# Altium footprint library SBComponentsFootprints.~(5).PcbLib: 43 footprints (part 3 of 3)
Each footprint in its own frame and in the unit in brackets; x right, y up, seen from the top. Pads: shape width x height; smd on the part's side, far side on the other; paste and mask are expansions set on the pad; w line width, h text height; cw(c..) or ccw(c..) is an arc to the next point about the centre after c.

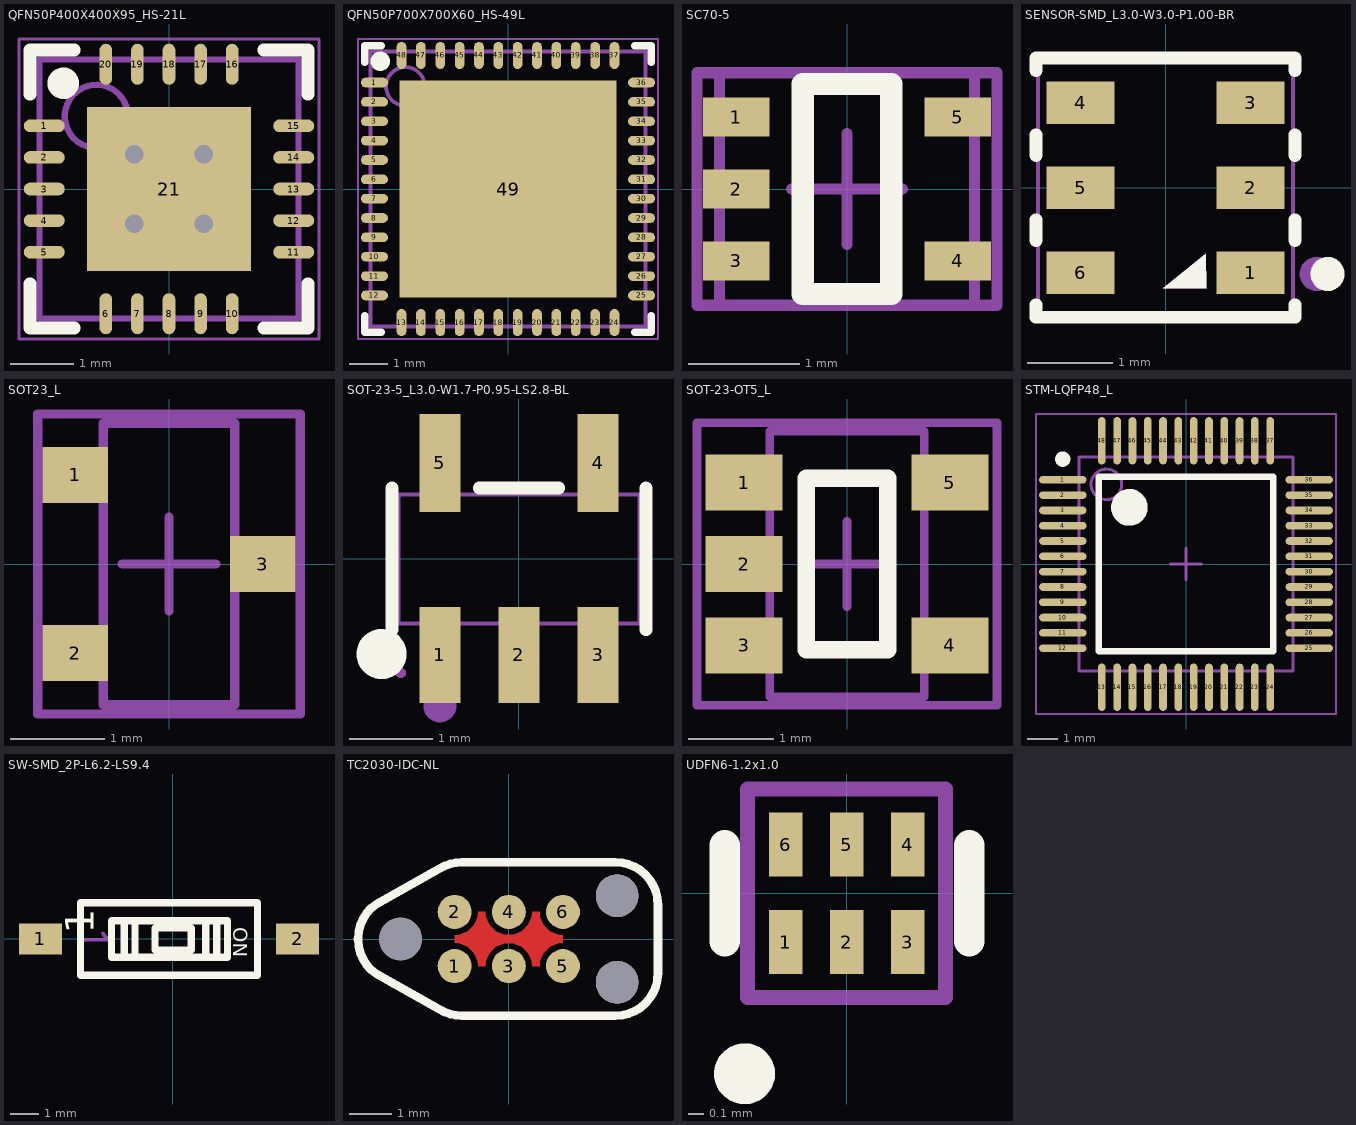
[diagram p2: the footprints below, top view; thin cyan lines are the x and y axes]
## QFN50P400X400X95_HS-21L [mm] "QFN, 20-Leads, Body 4,00x4,00mm, Pitch 0,50mm, Thermal Pad 2,60x2,60mm, IPC High Density"
height 0.95
pads (21):
  oval 0.65x0.2 smd: 1(-1.975,1) 2(-1.975,0.5) 3(-1.975,0) 4(-1.975,-0.5) 5(-1.975,-1) 11(1.975,-1) 12(1.975,-0.5) 13(1.975,0) 14(1.975,0.5) 15(1.975,1)
  oval 0.2x0.65 smd: 6(-1,-1.975) 7(-0.5,-1.975) 8(0,-1.975) 9(0.5,-1.975) 10(1,-1.975) 16(1,1.975) 17(0.5,1.975) 18(0,1.975) 19(-0.5,1.975) 20(-1,1.975)
  rect 2.6x2.6 smd: 21(0,0)
via -0.55,0.55 diameter 0.6 hole 0.3
via 0.55,0.55 diameter 0.6 hole 0.3
via -0.55,-0.55 diameter 0.6 hole 0.3
via 0.55,-0.55 diameter 0.6 hole 0.3
Top Overlay:
  circle w0.25: c-1.675,1.675 r0.125
  lines w0.2: -2.2,-1.5 -2.2,-2.2 -1.5,-2.2 ; -2.2,1.5 -2.2,2.2 -1.5,2.2 ; 1.5,-2.2 2.2,-2.2 2.2,-1.5 ; 1.5,2.2 2.2,2.2 2.2,1.5
Mechanical 13:
  circle w0.1: c-1.15,1.15 r0.5
  lines w0.1: -2.05,-2.05 -2.05,2.05 2.05,2.05 2.05,-2.05 -2.05,-2.05
Mechanical 15:
  lines w0.05: -2.375,-2.375 -2.375,2.375 2.375,2.375 2.375,-2.375 -2.375,-2.375
  lines w0.1: -0.5,0 0.5,0 ; 0,-0.5 0,0.5
3D body: height 0.95, standoff 0.05, extent -2.05,-2.05 2.05,2.05

## QFN50P700X700X60_HS-49L [mm] "QFN, 48-Leads, Body 7,00x7,00mm, Pitch 0,50mm, Thermal Pad 5,60x5,60mm, IPC High Density"
height 0.6
pads (49):
  oval 0.7x0.25 smd: 1(-3.45,2.75) 2(-3.45,2.25) 3(-3.45,1.75) 4(-3.45,1.25) 5(-3.45,0.75) 6(-3.45,0.25) 7(-3.45,-0.25) 8(-3.45,-0.75) 9(-3.45,-1.25) 10(-3.45,-1.75) 11(-3.45,-2.25) 12(-3.45,-2.75) 25(3.45,-2.75) 26(3.45,-2.25) 27(3.45,-1.75) 28(3.45,-1.25) 29(3.45,-0.75) 30(3.45,-0.25) 31(3.45,0.25) 32(3.45,0.75) 33(3.45,1.25) 34(3.45,1.75) 35(3.45,2.25) 36(3.45,2.75)
  oval 0.25x0.7 smd: 13(-2.75,-3.45) 14(-2.25,-3.45) 15(-1.75,-3.45) 16(-1.25,-3.45) 17(-0.75,-3.45) 18(-0.25,-3.45) 19(0.25,-3.45) 20(0.75,-3.45) 21(1.25,-3.45) 22(1.75,-3.45) 23(2.25,-3.45) 24(2.75,-3.45) 37(2.75,3.45) 38(2.25,3.45) 39(1.75,3.45) 40(1.25,3.45) 41(0.75,3.45) 42(0.25,3.45) 43(-0.25,3.45) 44(-0.75,3.45) 45(-1.25,3.45) 46(-1.75,3.45) 47(-2.25,3.45) 48(-2.75,3.45)
  rect 5.6x5.6 smd: 49(0,0)
Top Overlay:
  circle w0.25: c-3.3,3.3 r0.125
  lines w0.2: -3.7,-3.275 -3.7,-3.7 -3.275,-3.7 ; -3.7,3.275 -3.7,3.7 -3.275,3.7 ; 3.275,-3.7 3.7,-3.7 3.7,-3.275 ; 3.275,3.7 3.7,3.7 3.7,3.275
Mechanical 13:
  circle w0.1: c-2.65,2.65 r0.5
  lines w0.1: -3.55,-3.55 -3.55,3.55 3.55,3.55 3.55,-3.55 -3.55,-3.55
Mechanical 15:
  lines w0.05: -3.875,-3.875 -3.875,3.875 3.875,3.875 3.875,-3.875 -3.875,-3.875
  lines w0.1: -0.5,0 0.5,0 ; 0,-0.5 0,0.5
3D body: height 0.6, standoff 0.05, extent -3.55,-3.55 3.55,3.55

## SC70-5 [mm]
height 1.1
pads (5):
  rect 0.6x0.35 smd: 1(-1,0.65) 2(-1,0) 3(-1,-0.65) 4(1,-0.65) 5(1,0.65)
Top Overlay:
  lines w0.2: -0.4,-0.95 -0.4,0.95 0.4,0.95 0.4,-0.95 -0.4,-0.95
Mechanical 13:
  lines w0.1: -1.15,-1.05 1.15,-1.05 1.15,1.05 -1.15,1.05 -1.15,-1.05
Mechanical 15:
  lines w0.1: -0.5,0 0.5,0 ; 0,-0.5 0,0.5 ; -1.355,-1.05 1.355,-1.05 1.355,1.05 -1.355,1.05 -1.355,-1.05
3D body "User Library-sot353.step": height 1, standoff 0, extent -1.15,-1.05 1.15,1.05

## SENSOR-SMD_L3.0-W3.0-P1.00-BR [mm]
pads (6):
  rect 0.8x0.5 smd paste+0 mask+0.05: 1(1,-1) 2(1,0) 3(1,1) 4(-1,1) 5(-1,0) 6(-1,-1)
Top Overlay:
  circle w0.2: c1.905,-1.016 r0.1
  region: -0.028,-1.186 0.481,-1.187 0.476,-0.78
  lines w0.15: -1.524,-1.378 -1.524,-1.524 1.524,-1.524 1.524,-1.378 ; -1.524,-0.622 -1.524,-0.378 ; -1.524,0.378 -1.524,0.622 ; -1.524,1.378 -1.524,1.524 1.524,1.524 1.524,1.378 ; 1.524,-0.622 1.524,-0.378 ; 1.524,0.378 1.524,0.622
Mechanical 6:
  circle w0.2: c1.778,-1.016 r0.1
  region: -0.032,-1.186 0.477,-1.187 0.472,-0.781
Mechanical 15:
  region: 1.56,-1.5 1.559,-1.476 1.524,-1.443 1.476,-1.443 1.441,-1.476 1.44,-1.5 1.441,-1.524 1.476,-1.557 1.524,-1.557 1.559,-1.524
  region: -0.725,0.8 -1.275,0.8 -1.275,1.2 -0.725,1.2
  region: -0.725,-0.2 -1.275,-0.2 -1.275,0.2 -0.725,0.2
  region: -0.725,-1.2 -1.275,-1.2 -1.275,-0.8 -0.725,-0.8
  region: 1.275,-1.2 0.725,-1.2 0.725,-0.8 1.275,-0.8
  region: 1.275,-0.2 0.725,-0.2 0.725,0.2 1.275,0.2
  region: 1.275,0.8 0.725,0.8 0.725,1.2 1.275,1.2
  lines w0.051: -1.5,-1.5 -1.5,1.5 1.5,1.5 1.5,-1.5 -1.5,-1.5

## SOT23_L [mm] "SOT23, 3-Leads, Body 2.9x1.3mm, Pitch 0.95mm, Lead Span 2.3mm - Reverse Pinning, IPC High Density"
height 1.1
pads (3):
  rect 0.7x0.6 smd: 1(-1,0.95) 2(-1,-0.95) 3(1,0)
Mechanical 13:
  lines w0.1: -0.7,-1.5 0.7,-1.5 0.7,1.5 -0.7,1.5 -0.7,-1.5
Mechanical 15:
  lines w0.1: -0.5,0 0.5,0 ; 0,-0.5 0,0.5 ; -1.4,-1.6 1.4,-1.6 1.4,1.6 -1.4,1.6 -1.4,-1.6
3D body "SOT23.STEP": height 1.21, standoff -0.01, extent -1.125,-1.5 1.126,1.5

## SOT-23-5_L3.0-W1.7-P0.95-LS2.8-BL [mm]
pads (5):
  rect 0.49x1.157 smd: 1(-0.95,-1.154) 2(0,-1.154) 3(0.95,-1.154)
  rect 0.49x1.175 smd: 4(0.95,1.154) 5(-0.95,1.154)
Top Overlay:
  circle w0.3: c-1.651,-1.143 r0.15
  lines w0.152: -1.526,-0.851 -1.526,0.851 ; -0.476,0.851 0.476,0.851 ; 1.526,-0.851 1.526,0.851
Mechanical 6:
  circle w0.2: c-0.95,-1.763 r0.1
Mechanical 15:
  region: -1.36,-1.37 -1.361,-1.345 -1.396,-1.311 -1.445,-1.311 -1.48,-1.346 -1.48,-1.37 -1.48,-1.395 -1.445,-1.429 -1.396,-1.429 -1.361,-1.394
  region: -1.125,0.74 -1.125,1.01 -0.775,1.01 -0.775,0.74
  region: -1.125,1 -1.125,1.4 -0.775,1.4 -0.775,1
  region: 0.775,0.74 0.775,1.01 1.125,1.01 1.125,0.74
  region: 0.775,1 0.775,1.4 1.125,1.4 1.125,1
  region: 0.775,-1.01 0.775,-0.74 1.125,-0.74 1.125,-1.01
  region: 0.775,-1.4 0.775,-1 1.125,-1 1.125,-1.4
  region: -0.175,-1.01 -0.175,-0.74 0.175,-0.74 0.175,-1.01
  region: -0.175,-1.4 -0.175,-1 0.175,-1 0.175,-1.4
  region: -1.125,-1.01 -1.125,-0.74 -0.775,-0.74 -0.775,-1.01
  region: -1.125,-1.4 -1.125,-1 -0.775,-1 -0.775,-1.4
  lines w0.051: -1.45,-0.775 1.45,-0.775 1.45,0.775 -1.45,0.775 -1.45,-0.775

## SOT-23-OT5_L [mm] "SOT23, 5-Leads, Body 2.9x1.6mm, Pitch 0.95mm, Lead Span 2.7mm, IPC High Density"
height 1.45
pads (5):
  rect 0.9x0.65 smd: 1(-1.2,0.95) 2(-1.2,0) 3(-1.2,-0.95) 4(1.2,-0.95) 5(1.2,0.95)
Top Overlay:
  lines w0.2: -0.475,-1 -0.475,1 0.475,1 0.475,-1 -0.475,-1
Mechanical 13:
  lines w0.1: -0.9,-1.55 0.9,-1.55 0.9,1.55 -0.9,1.55 -0.9,-1.55
Mechanical 15:
  lines w0.1: -0.5,0 0.5,0 ; 0,-0.5 0,0.5 ; -1.75,-1.65 1.75,-1.65 1.75,1.65 -1.75,1.65 -1.75,-1.65
3D body: height 1.45, standoff 0, extent -0.9,-1.55 0.9,1.55

## STM-LQFP48_L [mm] "QFP, 48-Leads, Body 7x7mm, Pitch 0.5mm, IPC High Density"
height 1.6
pads (48):
  oval 1.55x0.25 smd: 1(-4.025,2.75) 2(-4.025,2.25) 3(-4.025,1.75) 4(-4.025,1.25) 5(-4.025,0.75) 6(-4.025,0.25) 7(-4.025,-0.25) 8(-4.025,-0.75) 9(-4.025,-1.25) 10(-4.025,-1.75) 11(-4.025,-2.25) 12(-4.025,-2.75) 25(4.025,-2.75) 26(4.025,-2.25) 27(4.025,-1.75) 28(4.025,-1.25) 29(4.025,-0.75) 30(4.025,-0.25) 31(4.025,0.25) 32(4.025,0.75) 33(4.025,1.25) 34(4.025,1.75) 35(4.025,2.25) 36(4.025,2.75)
  oval 0.25x1.55 smd: 13(-2.75,-4.025) 14(-2.25,-4.025) 15(-1.75,-4.025) 16(-1.25,-4.025) 17(-0.75,-4.025) 18(-0.25,-4.025) 19(0.25,-4.025) 20(0.75,-4.025) 21(1.25,-4.025) 22(1.75,-4.025) 23(2.25,-4.025) 24(2.75,-4.025) 37(2.75,4.025) 38(2.25,4.025) 39(1.75,4.025) 40(1.25,4.025) 41(0.75,4.025) 42(0.25,4.025) 43(-0.25,4.025) 44(-0.75,4.025) 45(-1.25,4.025) 46(-1.75,4.025) 47(-2.25,4.025) 48(-2.75,4.025)
Top Overlay:
  circle w0.6: c-1.85,1.85 r0.3
  circle w0.25: c-4.025,3.425 r0.125
  lines w0.2: -2.85,-2.85 2.85,-2.85 2.85,2.85 -2.85,2.85 -2.85,-2.85
Mechanical 13:
  circle w0.1: c-2.6,2.6 r0.5
  lines w0.1: -3.5,-3.5 3.5,-3.5 3.5,3.5 -3.5,3.5 -3.5,-3.5
Mechanical 15:
  lines w0.05: -4.9,-4.9 4.9,-4.9 4.9,4.9 -4.9,4.9 -4.9,-4.9
  lines w0.1: -0.5,0 0.5,0 ; 0,-0.5 0,0.5
3D body: height 1.6, standoff 0.05, extent -3.5,-3.5 3.5,3.5

## SW-SMD_2P-L6.2-LS9.4 [mm]
pads (2):
  rect 1.5x1.1 smd paste+0 mask+0.051: 1(-4.636,-0.002) 2(4.364,-0.002)
Top Overlay:
  lines w0.254: -1.706,-0.637 -1.706,0.633 ; -1.325,-0.637 -1.325,0.633 ; 1.152,-0.637 1.152,0.633 ; 1.533,-0.637 1.533,0.633 ; -3.236,-1.272 -3.236,1.268 2.964,1.268 2.964,-1.272 -3.236,-1.272 ; -2.15,-0.637 1.914,-0.637 1.914,0.633 -2.15,0.633 -2.15,-0.637 ; -0.626,-0.383 0.644,-0.383 0.644,0.379 -0.626,0.379 -0.626,-0.383
  text "ON" at 2.114,0.408 h0.5
  text "1" at -2.766,0.188 h1
Mechanical 15:
  region: -2.451,0.258 -2.471,0.258 -2.511,0.218 -2.491,0.148 -2.451,0.078 -2.391,0.018 -3.211,0.018 -3.221,0.028 -3.241,0.028 -3.271,-0.002 -3.271,-0.042 -3.261,-0.072 -3.231,-0.082 -2.241,-0.082 -2.226,-0.077 -2.216,-0.067 -2.206,-0.057 -2.201,-0.032 -2.211,-0.012 -2.231,0.018 -2.351,0.138 -2.411,0.238

## TC2030-IDC-NL [mm] "TagConnector TC2030-IDC-NL"
pads (9):
  round 0.8 smd paste-1: 1(-1.27,-0.635) 2(-1.27,0.635) 3(0,-0.635) 4(0,0.635) 5(1.27,-0.635) 6(1.27,0.635)
  round 1 hole 1 unplated mask+0: ""(-2.54,0) ""(2.54,-1.016) ""(2.54,1.016)
Top Layer:
  pour cut-out: -1.27,-0.085 -1.27,0.085 -1.163,0.096 -0.964,0.178 -0.813,0.329 -0.731,0.528 -0.72,0.635 -0.55,0.635 -0.539,0.528 -0.457,0.329 -0.306,0.178 -0.107,0.096 0.107,0.096 0.306,0.178 0.457,0.329 0.539,0.528 0.55,0.635 0.72,0.635 0.731,0.528 0.813,0.329 0.964,0.178 1.163,0.096 1.27,0.085 1.27,-0.085 1.163,-0.096 0.964,-0.178 0.813,-0.329 0.731,-0.528 0.72,-0.635 0.55,-0.635 0.539,-0.528 0.457,-0.329 0.306,-0.178 0.107,-0.096 -0.107,-0.096 -0.306,-0.178 -0.457,-0.329 -0.539,-0.528 -0.55,-0.635 -0.72,-0.635 -0.731,-0.528 -0.813,-0.329 -0.964,-0.178 -1.163,-0.096
Top Overlay:
  lines w0.2: -3.111,-0.816 cw(c-2.544,0) -3.111,0.816 -1.63,1.648 cw(c-1.1,0.8) -1.1,1.8 2.5,1.8 cw(c2.5,0.8) 3.5,0.8 3.5,-0.8 cw(c2.5,-0.8) 2.5,-1.8 -1.1,-1.8 cw(c-1.1,-0.8) -1.63,-1.648 -3.111,-0.816
Mechanical 15:
  lines w0.1: -3.111,-0.816 cw(c-2.544,0) -3.111,0.816 -1.63,1.648 cw(c-1.1,0.8) -1.1,1.8 2.5,1.8 cw(c2.5,0.8) 3.5,0.8 3.5,-0.8 cw(c2.5,-0.8) 2.5,-1.8 -1.1,-1.8 cw(c-1.1,-0.8) -1.63,-1.648 -3.111,-0.816
3D body: height 0, standoff 0, extent 0.873,0.236 1.67,1.034
3D body: height 0, standoff 0, extent 0.87,-1.034 1.667,-0.236
3D body: height 0, standoff 0, extent -1.67,-1.034 -0.873,-0.236
3D body: height 0, standoff 0, extent -0.4,-1.034 0.397,-0.236
3D body: height 0, standoff 0, extent -0.397,0.236 0.4,1.034
3D body: height 0, standoff 0, extent -1.667,0.236 -0.87,1.034

## UDFN6-1.2x1.0 [mm]
height 0.55
pads (6):
  rect 0.22x0.42 smd: 1(-0.4,-0.32) 2(0,-0.32) 3(0.4,-0.32) 4(0.4,0.32) 5(0,0.32) 6(-0.4,0.32)
Top Overlay:
  circle w0.2: c-0.67,-1.185 r0.1
  lines w0.2: -0.8,-0.315 -0.8,0.315 ; 0.805,-0.315 0.805,0.315
Mechanical 13:
  lines w0.1: -0.65,-0.685 -0.65,0.685 0.65,0.685 0.65,-0.685 -0.65,-0.685
3D body: height 0.55, standoff 0, extent -0.6,-0.5 0.6,0.5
